VERSION 5.8 ;
BUSBITCHARS "[]" ;
DIVIDERCHAR "/" ;
UNITS
    DATABASE MICRONS 1000 ;
END UNITS

VIA PLL_ANALOG_MACRO_via1_2_2200_440_1_5_410_410
  VIARULE via1Array ;
  CUTSIZE 0.19 0.19 ;
  LAYERS Metal1 Via1 Metal2 ;
  CUTSPACING 0.22 0.22 ;
  ENCLOSURE 0.05 0.125 0.005 0.05 ;
  ROWCOL 1 5 ;
END PLL_ANALOG_MACRO_via1_2_2200_440_1_5_410_410

VIA PLL_ANALOG_MACRO_via2_3_2200_440_1_5_410_410
  VIARULE via2Array ;
  CUTSIZE 0.19 0.19 ;
  LAYERS Metal2 Via2 Metal3 ;
  CUTSPACING 0.22 0.22 ;
  ENCLOSURE 0.005 0.05 0.05 0.005 ;
  ROWCOL 1 5 ;
END PLL_ANALOG_MACRO_via2_3_2200_440_1_5_410_410

VIA PLL_ANALOG_MACRO_via3_4_2200_440_1_5_410_410
  VIARULE via3Array ;
  CUTSIZE 0.19 0.19 ;
  LAYERS Metal3 Via3 Metal4 ;
  CUTSPACING 0.22 0.22 ;
  ENCLOSURE 0.05 0.005 0.005 0.05 ;
  ROWCOL 1 5 ;
END PLL_ANALOG_MACRO_via3_4_2200_440_1_5_410_410

VIA PLL_ANALOG_MACRO_via4_5_2200_440_1_5_410_410
  VIARULE via4Array ;
  CUTSIZE 0.19 0.19 ;
  LAYERS Metal4 Via4 Metal5 ;
  CUTSPACING 0.22 0.22 ;
  ENCLOSURE 0.005 0.05 0.05 0.005 ;
  ROWCOL 1 5 ;
END PLL_ANALOG_MACRO_via4_5_2200_440_1_5_410_410

VIA PLL_ANALOG_MACRO_via5_6_2200_440_1_2_840_840
  VIARULE viaTop1Array ;
  CUTSIZE 0.42 0.42 ;
  LAYERS Metal5 TopVia1 TopMetal1 ;
  CUTSPACING 0.42 0.42 ;
  ENCLOSURE 0.1 0.1 0.47 0.42 ;
  ROWCOL 1 2 ;
END PLL_ANALOG_MACRO_via5_6_2200_440_1_2_840_840

VIA PLL_ANALOG_MACRO_via6_7_5000_5000_2_2_1960_1960
  VIARULE viaTop2Array ;
  CUTSIZE 0.9 0.9 ;
  LAYERS TopMetal1 TopVia2 TopMetal2 ;
  CUTSPACING 1.06 1.06 ;
  ENCLOSURE 1.07 0.5 0.5 1.07 ;
  ROWCOL 2 2 ;
END PLL_ANALOG_MACRO_via6_7_5000_5000_2_2_1960_1960

VIA PLL_ANALOG_MACRO_via6_7_5000_2200_1_2_1960_1960
  VIARULE viaTop2Array ;
  CUTSIZE 0.9 0.9 ;
  LAYERS TopMetal1 TopVia2 TopMetal2 ;
  CUTSPACING 1.06 1.06 ;
  ENCLOSURE 1.07 0.5 0.5 0.65 ;
  ROWCOL 1 2 ;
END PLL_ANALOG_MACRO_via6_7_5000_2200_1_2_1960_1960

VIA PLL_ANALOG_MACRO_via6_7_2200_5000_2_1_1960_1960
  VIARULE viaTop2Array ;
  CUTSIZE 0.9 0.9 ;
  LAYERS TopMetal1 TopVia2 TopMetal2 ;
  CUTSPACING 1.06 1.06 ;
  ENCLOSURE 0.65 0.5 0.5 1.07 ;
  ROWCOL 2 1 ;
END PLL_ANALOG_MACRO_via6_7_2200_5000_2_1_1960_1960

VIA PLL_ANALOG_MACRO_via6_7_2200_2200_1_1_1960_1960
  VIARULE viaTop2Array ;
  CUTSIZE 0.9 0.9 ;
  LAYERS TopMetal1 TopVia2 TopMetal2 ;
  CUTSPACING 1.06 1.06 ;
  ENCLOSURE 0.65 0.5 0.5 0.65 ;
END PLL_ANALOG_MACRO_via6_7_2200_2200_1_1_1960_1960

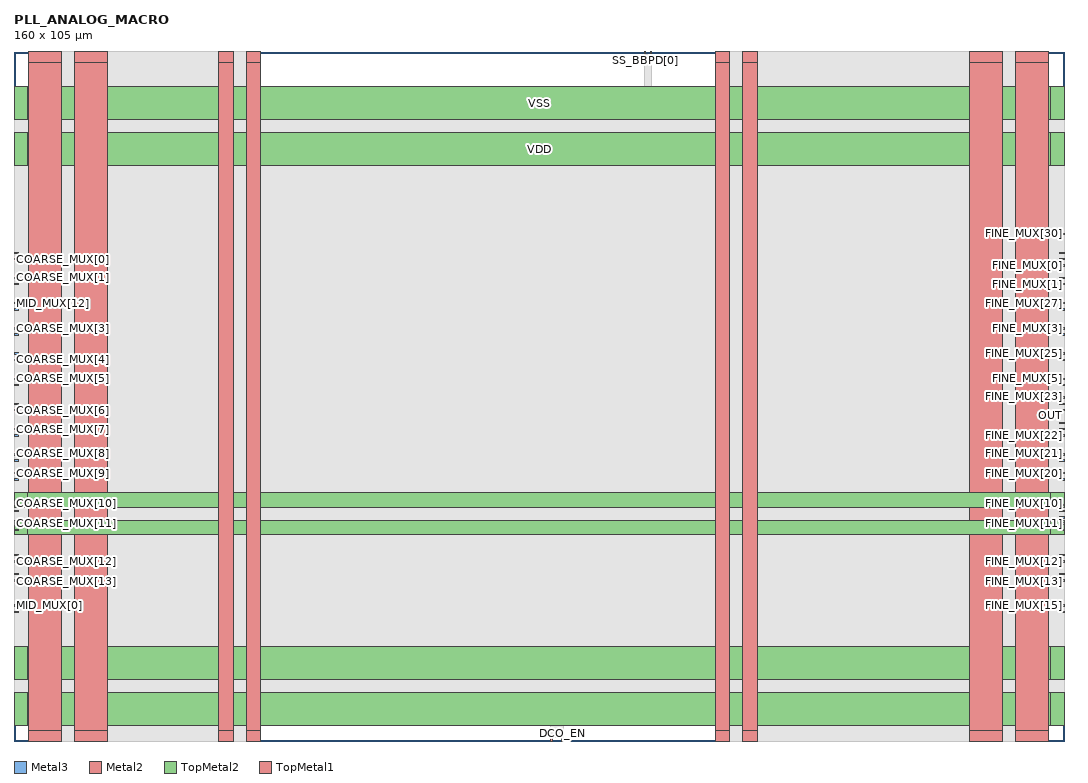
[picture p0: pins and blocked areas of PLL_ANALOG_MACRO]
MACRO PLL_ANALOG_MACRO
  FOREIGN PLL_ANALOG_MACRO 0 0 ;
  CLASS BLOCK ;
  SIZE 160 BY 105 ;
  PIN COARSE_MUX[0]
    DIRECTION INPUT ;
    USE SIGNAL ;
    PORT
      LAYER Metal3 ;
        RECT  0 73.34 0.72 73.54 ;
    END
  END COARSE_MUX[0]
  PIN COARSE_MUX[10]
    DIRECTION INPUT ;
    USE SIGNAL ;
    PORT
      LAYER Metal3 ;
        RECT  0 34.94 0.72 35.14 ;
    END
  END COARSE_MUX[10]
  PIN COARSE_MUX[11]
    DIRECTION INPUT ;
    USE SIGNAL ;
    PORT
      LAYER Metal3 ;
        RECT  0 33.02 0.72 33.22 ;
    END
  END COARSE_MUX[11]
  PIN COARSE_MUX[12]
    DIRECTION INPUT ;
    USE SIGNAL ;
    PORT
      LAYER Metal3 ;
        RECT  0 27.26 0.72 27.46 ;
    END
  END COARSE_MUX[12]
  PIN COARSE_MUX[13]
    DIRECTION INPUT ;
    USE SIGNAL ;
    PORT
      LAYER Metal3 ;
        RECT  0 25.34 0.72 25.54 ;
    END
  END COARSE_MUX[13]
  PIN COARSE_MUX[14]
    DIRECTION INPUT ;
    USE SIGNAL ;
    PORT
      LAYER Metal3 ;
        RECT  0 19.58 0.72 19.78 ;
    END
  END COARSE_MUX[14]
  PIN COARSE_MUX[1]
    DIRECTION INPUT ;
    USE SIGNAL ;
    PORT
      LAYER Metal3 ;
        RECT  0 70.46 0.72 70.66 ;
    END
  END COARSE_MUX[1]
  PIN COARSE_MUX[2]
    DIRECTION INPUT ;
    USE SIGNAL ;
    PORT
      LAYER Metal3 ;
        RECT  0 65.66 0.72 65.86 ;
    END
  END COARSE_MUX[2]
  PIN COARSE_MUX[3]
    DIRECTION INPUT ;
    USE SIGNAL ;
    PORT
      LAYER Metal3 ;
        RECT  0 62.78 0.72 62.98 ;
    END
  END COARSE_MUX[3]
  PIN COARSE_MUX[4]
    DIRECTION INPUT ;
    USE SIGNAL ;
    PORT
      LAYER Metal3 ;
        RECT  0 57.98 0.72 58.18 ;
    END
  END COARSE_MUX[4]
  PIN COARSE_MUX[5]
    DIRECTION INPUT ;
    USE SIGNAL ;
    PORT
      LAYER Metal3 ;
        RECT  0 55.1 0.72 55.3 ;
    END
  END COARSE_MUX[5]
  PIN COARSE_MUX[6]
    DIRECTION INPUT ;
    USE SIGNAL ;
    PORT
      LAYER Metal3 ;
        RECT  0 50.3 0.72 50.5 ;
    END
  END COARSE_MUX[6]
  PIN COARSE_MUX[7]
    DIRECTION INPUT ;
    USE SIGNAL ;
    PORT
      LAYER Metal3 ;
        RECT  0 47.42 0.72 47.62 ;
    END
  END COARSE_MUX[7]
  PIN COARSE_MUX[8]
    DIRECTION INPUT ;
    USE SIGNAL ;
    PORT
      LAYER Metal3 ;
        RECT  0 42.62 0.72 42.82 ;
    END
  END COARSE_MUX[8]
  PIN COARSE_MUX[9]
    DIRECTION INPUT ;
    USE SIGNAL ;
    PORT
      LAYER Metal3 ;
        RECT  0 40.7 0.72 40.9 ;
    END
  END COARSE_MUX[9]
  PIN DCO_EN
    DIRECTION INPUT ;
    USE SIGNAL ;
    PORT
      LAYER Metal2 ;
        RECT  83.48 0 83.68 0.72 ;
    END
  END DCO_EN
  PIN FINE_MUX[0]
    DIRECTION INPUT ;
    USE SIGNAL ;
    PORT
      LAYER Metal3 ;
        RECT  159.28 72.38 160 72.58 ;
    END
  END FINE_MUX[0]
  PIN FINE_MUX[10]
    DIRECTION INPUT ;
    USE SIGNAL ;
    PORT
      LAYER Metal3 ;
        RECT  159.28 34.94 160 35.14 ;
    END
  END FINE_MUX[10]
  PIN FINE_MUX[11]
    DIRECTION INPUT ;
    USE SIGNAL ;
    PORT
      LAYER Metal3 ;
        RECT  159.28 33.02 160 33.22 ;
    END
  END FINE_MUX[11]
  PIN FINE_MUX[12]
    DIRECTION INPUT ;
    USE SIGNAL ;
    PORT
      LAYER Metal3 ;
        RECT  159.28 27.26 160 27.46 ;
    END
  END FINE_MUX[12]
  PIN FINE_MUX[13]
    DIRECTION INPUT ;
    USE SIGNAL ;
    PORT
      LAYER Metal3 ;
        RECT  159.28 25.34 160 25.54 ;
    END
  END FINE_MUX[13]
  PIN FINE_MUX[14]
    DIRECTION INPUT ;
    USE SIGNAL ;
    PORT
      LAYER Metal3 ;
        RECT  159.28 19.58 160 19.78 ;
    END
  END FINE_MUX[14]
  PIN FINE_MUX[15]
    DIRECTION INPUT ;
    USE SIGNAL ;
    PORT
      LAYER Metal3 ;
        RECT  159.28 20.54 160 20.74 ;
    END
  END FINE_MUX[15]
  PIN FINE_MUX[16]
    DIRECTION INPUT ;
    USE SIGNAL ;
    PORT
      LAYER Metal3 ;
        RECT  159.28 24.38 160 24.58 ;
    END
  END FINE_MUX[16]
  PIN FINE_MUX[17]
    DIRECTION INPUT ;
    USE SIGNAL ;
    PORT
      LAYER Metal3 ;
        RECT  159.28 28.22 160 28.42 ;
    END
  END FINE_MUX[17]
  PIN FINE_MUX[18]
    DIRECTION INPUT ;
    USE SIGNAL ;
    PORT
      LAYER Metal3 ;
        RECT  159.28 32.06 160 32.26 ;
    END
  END FINE_MUX[18]
  PIN FINE_MUX[19]
    DIRECTION INPUT ;
    USE SIGNAL ;
    PORT
      LAYER Metal3 ;
        RECT  159.28 35.9 160 36.1 ;
    END
  END FINE_MUX[19]
  PIN FINE_MUX[1]
    DIRECTION INPUT ;
    USE SIGNAL ;
    PORT
      LAYER Metal3 ;
        RECT  159.28 69.5 160 69.7 ;
    END
  END FINE_MUX[1]
  PIN FINE_MUX[20]
    DIRECTION INPUT ;
    USE SIGNAL ;
    PORT
      LAYER Metal3 ;
        RECT  159.28 40.7 160 40.9 ;
    END
  END FINE_MUX[20]
  PIN FINE_MUX[21]
    DIRECTION INPUT ;
    USE SIGNAL ;
    PORT
      LAYER Metal3 ;
        RECT  159.28 42.62 160 42.82 ;
    END
  END FINE_MUX[21]
  PIN FINE_MUX[22]
    DIRECTION INPUT ;
    USE SIGNAL ;
    PORT
      LAYER Metal3 ;
        RECT  159.28 46.46 160 46.66 ;
    END
  END FINE_MUX[22]
  PIN FINE_MUX[23]
    DIRECTION INPUT ;
    USE SIGNAL ;
    PORT
      LAYER Metal3 ;
        RECT  159.28 51.26 160 51.46 ;
    END
  END FINE_MUX[23]
  PIN FINE_MUX[24]
    DIRECTION INPUT ;
    USE SIGNAL ;
    PORT
      LAYER Metal3 ;
        RECT  159.28 54.14 160 54.34 ;
    END
  END FINE_MUX[24]
  PIN FINE_MUX[25]
    DIRECTION INPUT ;
    USE SIGNAL ;
    PORT
      LAYER Metal3 ;
        RECT  159.28 58.94 160 59.14 ;
    END
  END FINE_MUX[25]
  PIN FINE_MUX[26]
    DIRECTION INPUT ;
    USE SIGNAL ;
    PORT
      LAYER Metal3 ;
        RECT  159.28 61.82 160 62.02 ;
    END
  END FINE_MUX[26]
  PIN FINE_MUX[27]
    DIRECTION INPUT ;
    USE SIGNAL ;
    PORT
      LAYER Metal3 ;
        RECT  159.28 66.62 160 66.82 ;
    END
  END FINE_MUX[27]
  PIN FINE_MUX[28]
    DIRECTION INPUT ;
    USE SIGNAL ;
    PORT
      LAYER Metal3 ;
        RECT  159.28 70.46 160 70.66 ;
    END
  END FINE_MUX[28]
  PIN FINE_MUX[29]
    DIRECTION INPUT ;
    USE SIGNAL ;
    PORT
      LAYER Metal3 ;
        RECT  159.28 73.34 160 73.54 ;
    END
  END FINE_MUX[29]
  PIN FINE_MUX[2]
    DIRECTION INPUT ;
    USE SIGNAL ;
    PORT
      LAYER Metal3 ;
        RECT  159.28 65.66 160 65.86 ;
    END
  END FINE_MUX[2]
  PIN FINE_MUX[30]
    DIRECTION INPUT ;
    USE SIGNAL ;
    PORT
      LAYER Metal3 ;
        RECT  159.28 77.18 160 77.38 ;
    END
  END FINE_MUX[30]
  PIN FINE_MUX[3]
    DIRECTION INPUT ;
    USE SIGNAL ;
    PORT
      LAYER Metal3 ;
        RECT  159.28 62.78 160 62.98 ;
    END
  END FINE_MUX[3]
  PIN FINE_MUX[4]
    DIRECTION INPUT ;
    USE SIGNAL ;
    PORT
      LAYER Metal3 ;
        RECT  159.28 57.98 160 58.18 ;
    END
  END FINE_MUX[4]
  PIN FINE_MUX[5]
    DIRECTION INPUT ;
    USE SIGNAL ;
    PORT
      LAYER Metal3 ;
        RECT  159.28 55.1 160 55.3 ;
    END
  END FINE_MUX[5]
  PIN FINE_MUX[6]
    DIRECTION INPUT ;
    USE SIGNAL ;
    PORT
      LAYER Metal3 ;
        RECT  159.28 50.3 160 50.5 ;
    END
  END FINE_MUX[6]
  PIN FINE_MUX[7]
    DIRECTION INPUT ;
    USE SIGNAL ;
    PORT
      LAYER Metal3 ;
        RECT  159.28 47.42 160 47.62 ;
    END
  END FINE_MUX[7]
  PIN FINE_MUX[8]
    DIRECTION INPUT ;
    USE SIGNAL ;
    PORT
      LAYER Metal3 ;
        RECT  159.28 43.58 160 43.78 ;
    END
  END FINE_MUX[8]
  PIN FINE_MUX[9]
    DIRECTION INPUT ;
    USE SIGNAL ;
    PORT
      LAYER Metal3 ;
        RECT  159.28 39.74 160 39.94 ;
    END
  END FINE_MUX[9]
  PIN INJ_EDGE
    DIRECTION OUTPUT ;
    USE SIGNAL ;
    PORT
      LAYER Metal3 ;
        RECT  159.28 33.98 160 34.18 ;
    END
  END INJ_EDGE
  PIN INJ_EN
    DIRECTION INPUT ;
    USE SIGNAL ;
    PORT
      LAYER Metal3 ;
        RECT  159.28 52.22 160 52.42 ;
    END
  END INJ_EN
  PIN MID_MUX[0]
    DIRECTION INPUT ;
    USE SIGNAL ;
    PORT
      LAYER Metal3 ;
        RECT  0 20.54 0.72 20.74 ;
    END
  END MID_MUX[0]
  PIN MID_MUX[10]
    DIRECTION INPUT ;
    USE SIGNAL ;
    PORT
      LAYER Metal3 ;
        RECT  0 58.94 0.72 59.14 ;
    END
  END MID_MUX[10]
  PIN MID_MUX[11]
    DIRECTION INPUT ;
    USE SIGNAL ;
    PORT
      LAYER Metal3 ;
        RECT  0 61.82 0.72 62.02 ;
    END
  END MID_MUX[11]
  PIN MID_MUX[12]
    DIRECTION INPUT ;
    USE SIGNAL ;
    PORT
      LAYER Metal3 ;
        RECT  0 66.62 0.72 66.82 ;
    END
  END MID_MUX[12]
  PIN MID_MUX[13]
    DIRECTION INPUT ;
    USE SIGNAL ;
    PORT
      LAYER Metal3 ;
        RECT  0 69.5 0.72 69.7 ;
    END
  END MID_MUX[13]
  PIN MID_MUX[14]
    DIRECTION INPUT ;
    USE SIGNAL ;
    PORT
      LAYER Metal3 ;
        RECT  0 74.3 0.72 74.5 ;
    END
  END MID_MUX[14]
  PIN MID_MUX[1]
    DIRECTION INPUT ;
    USE SIGNAL ;
    PORT
      LAYER Metal3 ;
        RECT  0 24.38 0.72 24.58 ;
    END
  END MID_MUX[1]
  PIN MID_MUX[2]
    DIRECTION INPUT ;
    USE SIGNAL ;
    PORT
      LAYER Metal3 ;
        RECT  0 28.22 0.72 28.42 ;
    END
  END MID_MUX[2]
  PIN MID_MUX[3]
    DIRECTION INPUT ;
    USE SIGNAL ;
    PORT
      LAYER Metal3 ;
        RECT  0 32.06 0.72 32.26 ;
    END
  END MID_MUX[3]
  PIN MID_MUX[4]
    DIRECTION INPUT ;
    USE SIGNAL ;
    PORT
      LAYER Metal3 ;
        RECT  0 35.9 0.72 36.1 ;
    END
  END MID_MUX[4]
  PIN MID_MUX[5]
    DIRECTION INPUT ;
    USE SIGNAL ;
    PORT
      LAYER Metal3 ;
        RECT  0 39.74 0.72 39.94 ;
    END
  END MID_MUX[5]
  PIN MID_MUX[6]
    DIRECTION INPUT ;
    USE SIGNAL ;
    PORT
      LAYER Metal3 ;
        RECT  0 43.58 0.72 43.78 ;
    END
  END MID_MUX[6]
  PIN MID_MUX[7]
    DIRECTION INPUT ;
    USE SIGNAL ;
    PORT
      LAYER Metal3 ;
        RECT  0 46.46 0.72 46.66 ;
    END
  END MID_MUX[7]
  PIN MID_MUX[8]
    DIRECTION INPUT ;
    USE SIGNAL ;
    PORT
      LAYER Metal3 ;
        RECT  0 51.26 0.72 51.46 ;
    END
  END MID_MUX[8]
  PIN MID_MUX[9]
    DIRECTION INPUT ;
    USE SIGNAL ;
    PORT
      LAYER Metal3 ;
        RECT  0 54.14 0.72 54.34 ;
    END
  END MID_MUX[9]
  PIN MID_OUT
    DIRECTION OUTPUT ;
    USE SIGNAL ;
    PORT
      LAYER Metal3 ;
        RECT  159.28 74.3 160 74.5 ;
    END
  END MID_OUT
  PIN OUT
    DIRECTION OUTPUT ;
    USE SIGNAL ;
    PORT
      LAYER Metal3 ;
        RECT  159.28 48.38 160 48.58 ;
    END
  END OUT
  PIN REF
    DIRECTION INPUT ;
    USE SIGNAL ;
    PORT
      LAYER Metal2 ;
        RECT  81.8 0 82 0.72 ;
    END
  END REF
  PIN SS_BBPD[0]
    DIRECTION OUTPUT ;
    USE SIGNAL ;
    PORT
      LAYER Metal2 ;
        RECT  96.08 104.28 96.28 105 ;
    END
  END SS_BBPD[0]
  PIN SS_BBPD[1]
    DIRECTION OUTPUT ;
    USE SIGNAL ;
    PORT
      LAYER Metal2 ;
        RECT  96.92 104.28 97.12 105 ;
    END
  END SS_BBPD[1]
  PIN VDD
    DIRECTION INOUT ;
    USE POWER ;
    PORT
      LAYER TopMetal2 ;
        RECT  158 31.4 160 33.6 ;
        RECT  0 31.4 2 33.6 ;
        RECT  0 31.4 160 33.6 ;
      LAYER TopMetal1 ;
        RECT  106.82 103.36 109.02 105 ;
        RECT  106.82 0 109.02 1.64 ;
        RECT  106.82 0 109.02 105 ;
        RECT  31.22 103.36 33.42 105 ;
        RECT  31.22 0 33.42 1.64 ;
        RECT  31.22 0 33.42 105 ;
      LAYER TopMetal2 ;
        RECT  158 87.66 160 92.66 ;
        RECT  0 87.66 2 92.66 ;
        RECT  0 87.66 160 92.66 ;
        RECT  158 9.4 160 14.4 ;
        RECT  0 9.4 2 14.4 ;
        RECT  0 9.4 160 14.4 ;
      LAYER TopMetal1 ;
        RECT  145.62 103.36 150.62 105 ;
        RECT  145.62 0 150.62 1.64 ;
        RECT  145.62 0 150.62 105 ;
        RECT  9.22 103.36 14.22 105 ;
        RECT  9.22 0 14.22 1.64 ;
        RECT  9.22 0 14.22 105 ;
    END
  END VDD
  PIN VSS
    DIRECTION INOUT ;
    USE GROUND ;
    PORT
      LAYER TopMetal2 ;
        RECT  158 35.6 160 37.8 ;
        RECT  0 35.6 2 37.8 ;
        RECT  0 35.6 160 37.8 ;
      LAYER TopMetal1 ;
        RECT  111.02 103.36 113.22 105 ;
        RECT  111.02 0 113.22 1.64 ;
        RECT  111.02 0 113.22 105 ;
        RECT  35.42 103.36 37.62 105 ;
        RECT  35.42 0 37.62 1.64 ;
        RECT  35.42 0 37.62 105 ;
      LAYER TopMetal2 ;
        RECT  158 94.66 160 99.66 ;
        RECT  0 94.66 2 99.66 ;
        RECT  0 94.66 160 99.66 ;
        RECT  158 2.4 160 7.4 ;
        RECT  0 2.4 2 7.4 ;
        RECT  0 2.4 160 7.4 ;
      LAYER TopMetal1 ;
        RECT  152.62 103.36 157.62 105 ;
        RECT  152.62 0 157.62 1.64 ;
        RECT  152.62 0 157.62 105 ;
        RECT  2.22 103.36 7.22 105 ;
        RECT  2.22 0 7.22 1.64 ;
        RECT  2.22 0 7.22 105 ;
    END
  END VSS
  OBS
    LAYER Metal1 ;
     RECT  18.72 18.68 141.12 83.38 ;
    LAYER Metal2 ;
     RECT  111.2 18.755 113.04 19.58 ;
     RECT  111.2 19.58 138.7 19.59 ;
     RECT  105.95 19.59 138.7 20.06 ;
     RECT  81.8 0.48 83.68 20.07 ;
     RECT  101.12 20.06 139.235 20.07 ;
     RECT  100.7 20.07 139.235 20.54 ;
     RECT  81.8 20.07 84.1 20.545 ;
     RECT  80.96 20.545 84.1 21.02 ;
     RECT  99.86 20.54 139.235 21.22 ;
     RECT  35.6 18.755 37.44 22.535 ;
     RECT  101.12 21.22 139.235 24.58 ;
     RECT  101.54 24.58 139.235 25.34 ;
     RECT  101.54 25.34 139.33 26.02 ;
     RECT  80.96 21.02 87.46 28.22 ;
     RECT  0.74 27.26 0.94 28.9 ;
     RECT  80.96 28.22 87.88 35.665 ;
     RECT  80.96 35.665 89.86 36.86 ;
     RECT  80.96 36.86 90.4 40.7 ;
     RECT  101.54 26.02 139.235 40.7 ;
     RECT  80.96 40.7 139.33 41.38 ;
     RECT  80.96 41.38 139.235 49.82 ;
     RECT  80.12 49.82 139.235 50.795 ;
     RECT  79.135 50.795 139.235 51.46 ;
     RECT  82.64 51.46 139.235 55.58 ;
     RECT  82.64 55.58 139.33 56.26 ;
     RECT  82.64 56.26 139.235 58.18 ;
     RECT  83.48 58.18 139.235 62.98 ;
     RECT  83.48 62.98 86.2 63.94 ;
     RECT  83.48 63.94 84.52 69.22 ;
     RECT  83.48 69.22 84.1 70.18 ;
     RECT  96.08 62.98 139.235 74.5 ;
     RECT  96.08 74.5 131.14 74.88 ;
     RECT  96.08 74.88 127.36 75.45 ;
     RECT  31.4 22.535 37.44 79.525 ;
     RECT  96.08 75.45 113.04 79.525 ;
     RECT  96.08 79.525 108.84 82.66 ;
     RECT  31.4 79.525 33.24 83.305 ;
     RECT  107 82.66 108.84 83.305 ;
     RECT  96.08 82.66 97.12 104.64 ;
    LAYER Metal3 ;
     RECT  0.32 21.98 0.42 29.86 ;
     RECT  0.42 19.58 3.46 74.5 ;
     RECT  3.46 20.54 31.355 74.5 ;
     RECT  31.355 20.54 31.4 83.26 ;
     RECT  31.4 19.58 33.285 83.26 ;
     RECT  33.285 19.58 35.555 79.48 ;
     RECT  35.555 18.8 37.485 79.48 ;
     RECT  37.485 19.58 101.54 74.98 ;
     RECT  101.54 19.58 106.955 77.86 ;
     RECT  106.955 19.58 108.885 83.26 ;
     RECT  108.885 19.58 111.155 79.48 ;
     RECT  111.155 18.8 113.085 79.48 ;
     RECT  113.085 19.58 134.82 77.86 ;
     RECT  134.82 20.54 144.8 77.86 ;
     RECT  144.8 19.58 145 77.86 ;
     RECT  145 19.58 159.6 77.38 ;
     RECT  159.6 44.54 159.7 60.1 ;
     RECT  159.6 70.94 159.7 75.46 ;
    LAYER Metal4 ;
     RECT  3.26 19.11 3.46 19.68 ;
     RECT  111.2 18.755 113.04 20.06 ;
     RECT  134.72 19.11 134.92 20.54 ;
     RECT  151.1 20.06 151.3 20.74 ;
     RECT  35.6 18.755 37.44 22.535 ;
     RECT  6.2 24.86 6.4 25.54 ;
     RECT  151.94 25.34 152.14 30.34 ;
     RECT  107 20.06 113.04 33.98 ;
     RECT  107 33.98 122.74 35.43 ;
     RECT  134.72 20.54 139.12 35.43 ;
     RECT  103.22 35.43 122.74 36 ;
     RECT  134.72 35.43 147.94 36 ;
     RECT  107 36 122.74 37.06 ;
     RECT  134.72 36 139.12 41.67 ;
     RECT  132.2 41.67 139.12 42.24 ;
     RECT  107 37.06 113.5 42.82 ;
     RECT  80.12 50.31 80.32 50.88 ;
     RECT  154.46 50.78 154.66 52.42 ;
     RECT  83.06 53.18 83.68 54.82 ;
     RECT  83.06 54.82 83.26 55.3 ;
     RECT  107 42.82 113.04 61.35 ;
     RECT  134.72 42.24 139.12 61.35 ;
     RECT  107 61.35 113.5 61.92 ;
     RECT  134.72 61.35 145 61.92 ;
     RECT  134.72 61.92 139.12 68.06 ;
     RECT  132.2 68.06 139.12 73.06 ;
     RECT  3.26 32.55 3.46 73.44 ;
     RECT  132.2 73.06 134.92 73.54 ;
     RECT  31.4 22.535 37.44 79.525 ;
     RECT  107 61.92 113.04 79.525 ;
     RECT  31.4 79.525 33.24 83.305 ;
     RECT  107 79.525 108.84 83.305 ;
    LAYER Metal5 ;
     RECT  3.26 19.58 6.2 19.78 ;
     RECT  3.26 33.02 6.2 73.54 ;
     RECT  6.2 19.58 31.355 73.54 ;
     RECT  31.355 19.58 33.285 83.47 ;
     RECT  33.285 19.58 35.555 79.69 ;
     RECT  35.555 18.59 37.485 79.69 ;
     RECT  37.485 19.58 106.955 73.54 ;
     RECT  106.955 19.58 108.885 83.47 ;
     RECT  108.885 19.58 111.155 79.69 ;
     RECT  111.155 18.59 113.085 79.69 ;
     RECT  113.085 19.58 134.92 73.54 ;
     RECT  134.92 20.06 139.12 20.74 ;
     RECT  134.92 61.82 145 62.02 ;
     RECT  134.92 35.9 147.94 36.1 ;
     RECT  139.12 20.06 151.3 20.26 ;
     RECT  134.92 50.78 154.66 50.98 ;
    LAYER TopMetal1 ;
     RECT  2.22 0 37.62 105 ;
     RECT  106.82 0 157.62 105 ;
    LAYER TopMetal2 ;
     RECT  0 2.4 160 99.66 ;
  END
END PLL_ANALOG_MACRO
END LIBRARY
